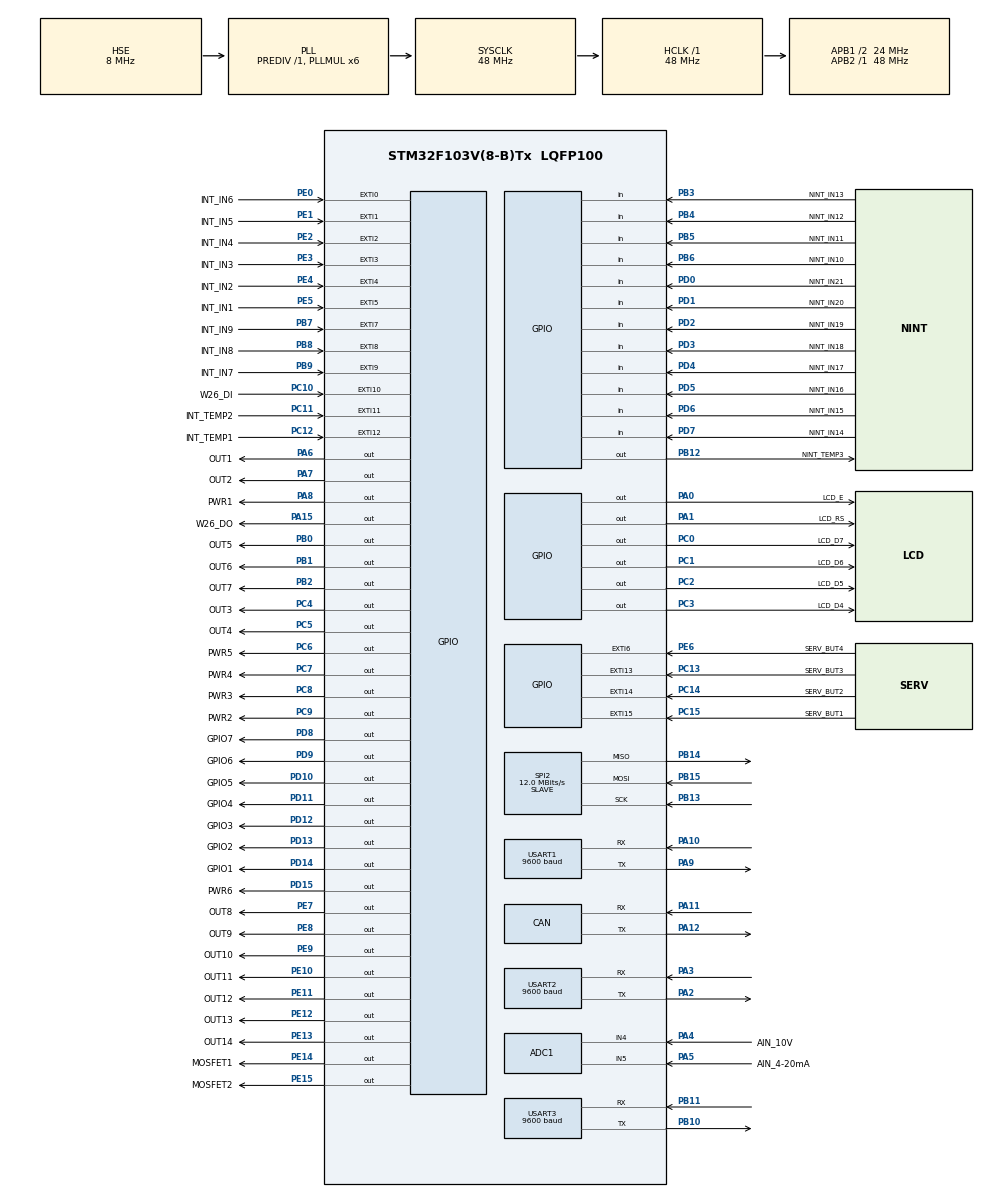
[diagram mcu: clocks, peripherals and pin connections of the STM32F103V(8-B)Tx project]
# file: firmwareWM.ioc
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ADC1.Channel-0\#ChannelRegularConversion=ADC_CHANNEL_TEMPSENSOR
ADC1.Channel-1\#ChannelInjectedConversion=ADC_CHANNEL_4
ADC1.Channel-2\#ChannelInjectedConversion=ADC_CHANNEL_5
ADC1.Channel-3\#ChannelInjectedConversion=ADC_CHANNEL_TEMPSENSOR
ADC1.Channel-4\#ChannelInjectedConversion=ADC_CHANNEL_VREFINT
ADC1.ContinuousConvMode=DISABLE
ADC1.DataAlign=ADC_DATAALIGN_RIGHT
ADC1.DiscontinuousConvMode=DISABLE
ADC1.EnableAnalogWatchDog=false
ADC1.EnableRegularConversion=ENABLE
ADC1.ExternalTrigConv=ADC_SOFTWARE_START
ADC1.ExternalTrigInjecConv=ADC_INJECTED_SOFTWARE_START
ADC1.InjNumberOfConversion=4
ADC1.InjectedConvMode=None
ADC1.InjectedOffset-1\#ChannelInjectedConversion=0
ADC1.InjectedOffset-2\#ChannelInjectedConversion=0
ADC1.InjectedOffset-3\#ChannelInjectedConversion=0
ADC1.InjectedOffset-4\#ChannelInjectedConversion=0
ADC1.NbrOfConversion=1
ADC1.Rank-0\#ChannelRegularConversion=1
ADC1.Rank-1\#ChannelInjectedConversion=1
ADC1.Rank-2\#ChannelInjectedConversion=2
ADC1.Rank-3\#ChannelInjectedConversion=3
ADC1.Rank-4\#ChannelInjectedConversion=4
ADC1.SamplingTime-0\#ChannelRegularConversion=ADC_SAMPLETIME_1CYCLE_5
ADC1.SamplingTime-1\#ChannelInjectedConversion=ADC_SAMPLETIME_1CYCLE_5
ADC1.SamplingTime-2\#ChannelInjectedConversion=ADC_SAMPLETIME_1CYCLE_5
ADC1.SamplingTime-3\#ChannelInjectedConversion=ADC_SAMPLETIME_7CYCLES_5
ADC1.SamplingTime-4\#ChannelInjectedConversion=ADC_SAMPLETIME_1CYCLE_5
ADC1.ScanConvMode=ADC_SCAN_ENABLE
ADC1.master=1
CAN.CalculateTimeBit=2000
CAN.CalculateTimeQuantum=666.6666666666666
IWDG.Prescaler=IWDG_PRESCALER_128
IWDG.Reload=1500
Mcu.Family=STM32F1
Mcu.Name=STM32F103V(8-B)Tx
Mcu.Package=LQFP100
NVIC.EXTI0_IRQn=true\:2\:0\:true\:false\:true\:true
NVIC.EXTI15_10_IRQn=true\:2\:0\:true\:false\:true\:true
NVIC.EXTI1_IRQn=true\:2\:0\:true\:false\:true\:true
NVIC.EXTI2_IRQn=true\:2\:0\:true\:false\:true\:true
NVIC.EXTI3_IRQn=true\:2\:0\:true\:false\:true\:true
NVIC.EXTI4_IRQn=true\:2\:0\:true\:false\:true\:true
NVIC.EXTI9_5_IRQn=true\:2\:0\:true\:false\:true\:true
NVIC.PriorityGroup=NVIC_PRIORITYGROUP_4
NVIC.TIM3_IRQn=true\:1\:0\:true\:false\:true\:true
NVIC.USART1_IRQn=true\:0\:0\:false\:false\:true\:true
NVIC.WWDG_IRQn=true\:0\:0\:false\:false\:true\:true
OSC_IN.Mode=HSE-External-Oscillator
OSC_IN.Signal=RCC_OSC_IN
OSC_OUT.Mode=HSE-External-Oscillator
OSC_OUT.Signal=RCC_OSC_OUT
PA0-WKUP.GPIO_Label=LCD_E
PA0-WKUP.Signal=GPIO_Output
PA1.GPIO_Label=LCD_RS
PA1.Signal=GPIO_Output
PA10.Mode=Asynchronous
PA10.Signal=USART1_RX
PA11.Mode=Master
PA11.Signal=CAN_RX
PA12.Mode=Master
PA12.Signal=CAN_TX
PA13.GPIO_Label=SWDIO
PA13.Mode=Serial_Wire
PA13.Signal=SYS_JTMS-SWDIO
PA14.GPIO_Label=SWCLK
PA14.Mode=Serial_Wire
PA14.Signal=SYS_JTCK-SWCLK
PA15.GPIO_Label=W26_DO
PA15.Signal=GPIO_Output
PA2.Mode=Asynchronous
PA2.Signal=USART2_TX
PA3.Mode=Asynchronous
PA3.Signal=USART2_RX
PA4.GPIO_Label=AIN_10V
PA4.Signal=ADCx_IN4
PA5.GPIO_Label=AIN_4-20mA
PA5.Signal=ADCx_IN5
PA6.GPIO_Label=OUT1
PA6.Signal=GPIO_Output
PA7.GPIO_Label=OUT2
PA7.Signal=GPIO_Output
PA8.GPIO_Label=PWR1
PA8.Signal=GPIO_Output
PA9.Mode=Asynchronous
PA9.Signal=USART1_TX
PB0.GPIO_Label=OUT5
PB0.Signal=GPIO_Output
PB1.GPIO_Label=OUT6
PB1.Signal=GPIO_Output
PB10.Mode=Asynchronous
PB10.Signal=USART3_TX
PB11.Mode=Asynchronous
PB11.Signal=USART3_RX
PB12.GPIO_Label=NINT_TEMP3
PB12.Signal=GPIO_Output
PB13.Mode=Full_Duplex_Slave
PB13.Signal=SPI2_SCK
PB14.Mode=Full_Duplex_Slave
PB14.Signal=SPI2_MISO
PB15.Mode=Full_Duplex_Slave
PB15.Signal=SPI2_MOSI
PB2.GPIO_Label=OUT7
PB2.Signal=GPIO_Output
PB3.GPIO_Label=NINT_IN13
PB3.GPIO_PuPd=GPIO_PULLUP
PB3.Signal=GPIO_Input
PB4.GPIO_Label=NINT_IN12
PB4.GPIO_PuPd=GPIO_PULLUP
PB4.Signal=GPIO_Input
PB5.GPIO_Label=NINT_IN11
PB5.GPIO_PuPd=GPIO_PULLUP
PB5.Signal=GPIO_Input
PB6.GPIO_Label=NINT_IN10
PB6.GPIO_PuPd=GPIO_PULLUP
PB6.Signal=GPIO_Input
PB7.GPIO_Label=INT_IN9
PB7.GPIO_PuPd=GPIO_PULLUP
PB7.Signal=GPXTI7
PB8.GPIO_Label=INT_IN8
PB8.GPIO_PuPd=GPIO_PULLUP
PB8.Signal=GPXTI8
PB9.GPIO_Label=INT_IN7
PB9.GPIO_PuPd=GPIO_PULLUP
PB9.Signal=GPXTI9
PC0.GPIO_Label=LCD_D7
PC0.Signal=GPIO_Output
PC1.GPIO_Label=LCD_D6
PC1.Signal=GPIO_Output
PC10.GPIO_Label=W26_DI
PC10.GPIO_PuPd=GPIO_PULLUP
PC10.Signal=GPXTI10
PC11.GPIO_Label=INT_TEMP2
PC11.GPIO_PuPd=GPIO_PULLUP
PC11.Signal=GPXTI11
PC12.GPIO_Label=INT_TEMP1
PC12.GPIO_PuPd=GPIO_PULLUP
PC12.Signal=GPXTI12
PC13-TAMPER-RTC.GPIO_Label=SERV_BUT3
PC13-TAMPER-RTC.GPIO_PuPd=GPIO_PULLUP
PC13-TAMPER-RTC.Signal=GPXTI13
PC14-OSC32_IN.GPIO_Label=SERV_BUT2
PC14-OSC32_IN.GPIO_PuPd=GPIO_PULLUP
PC14-OSC32_IN.Signal=GPXTI14
PC15-OSC32_OUT.GPIO_Label=SERV_BUT1
PC15-OSC32_OUT.GPIO_PuPd=GPIO_PULLUP
PC15-OSC32_OUT.Signal=GPXTI15
PC2.GPIO_Label=LCD_D5
PC2.Signal=GPIO_Output
PC3.GPIO_Label=LCD_D4
PC3.Signal=GPIO_Output
PC4.GPIO_Label=OUT3
PC4.Signal=GPIO_Output
PC5.GPIO_Label=OUT4
PC5.Signal=GPIO_Output
PC6.GPIO_Label=PWR5
PC6.Signal=GPIO_Output
PC7.GPIO_Label=PWR4
PC7.Signal=GPIO_Output
PC8.GPIO_Label=PWR3
PC8.Signal=GPIO_Output
PC9.GPIO_Label=PWR2
PC9.Signal=GPIO_Output
PD0.GPIO_Label=NINT_IN21
PD0.GPIO_PuPd=GPIO_PULLUP
PD0.Signal=GPIO_Input
PD1.GPIO_Label=NINT_IN20
PD1.GPIO_PuPd=GPIO_PULLUP
PD1.Signal=GPIO_Input
PD10.GPIO_Label=GPIO5
PD10.Signal=GPIO_Output
PD11.GPIO_Label=GPIO4
PD11.Signal=GPIO_Output
PD12.GPIO_Label=GPIO3
PD12.Signal=GPIO_Output
PD13.GPIO_Label=GPIO2
PD13.Signal=GPIO_Output
PD14.GPIO_Label=GPIO1
PD14.Signal=GPIO_Output
PD15.GPIO_Label=PWR6
PD15.Signal=GPIO_Output
PD2.GPIO_Label=NINT_IN19
PD2.GPIO_PuPd=GPIO_PULLUP
PD2.Signal=GPIO_Input
PD3.GPIO_Label=NINT_IN18
PD3.GPIO_PuPd=GPIO_PULLUP
PD3.Signal=GPIO_Input
PD4.GPIO_Label=NINT_IN17
PD4.GPIO_PuPd=GPIO_PULLUP
PD4.Signal=GPIO_Input
PD5.GPIO_Label=NINT_IN16
PD5.GPIO_PuPd=GPIO_PULLUP
PD5.Signal=GPIO_Input
PD6.GPIO_Label=NINT_IN15
PD6.GPIO_PuPd=GPIO_PULLUP
PD6.Signal=GPIO_Input
PD7.GPIO_Label=NINT_IN14
PD7.GPIO_PuPd=GPIO_PULLUP
PD7.Signal=GPIO_Input
PD8.GPIO_Label=GPIO7
PD8.Signal=GPIO_Output
PD9.GPIO_Label=GPIO6
PD9.Signal=GPIO_Output
PE0.GPIO_Label=INT_IN6
PE0.GPIO_PuPd=GPIO_PULLUP
PE0.Signal=GPXTI0
PE1.GPIO_Label=INT_IN5
PE1.GPIO_PuPd=GPIO_PULLUP
PE1.Signal=GPXTI1
PE10.GPIO_Label=OUT11
PE10.Signal=GPIO_Output
PE11.GPIO_Label=OUT12
PE11.Signal=GPIO_Output
PE12.GPIO_Label=OUT13
PE12.Signal=GPIO_Output
PE13.GPIO_Label=OUT14
PE13.Signal=GPIO_Output
PE14.GPIO_Label=MOSFET1
PE14.Signal=GPIO_Output
PE15.GPIO_Label=MOSFET2
PE15.Signal=GPIO_Output
PE2.GPIO_Label=INT_IN4
PE2.GPIO_PuPd=GPIO_NOPULL
PE2.Signal=GPXTI2
PE3.GPIO_Label=INT_IN3
PE3.GPIO_PuPd=GPIO_NOPULL
PE3.Signal=GPXTI3
PE4.GPIO_Label=INT_IN2
PE4.GPIO_PuPd=GPIO_NOPULL
PE4.Signal=GPXTI4
PE5.GPIO_Label=INT_IN1
PE5.Signal=GPXTI5
PE6.GPIO_Label=SERV_BUT4
PE6.GPIO_PuPd=GPIO_PULLUP
PE6.Signal=GPXTI6
PE7.GPIO_Label=OUT8
PE7.Signal=GPIO_Output
PE8.GPIO_Label=OUT9
PE8.Signal=GPIO_Output
PE9.GPIO_Label=OUT10
PE9.Signal=GPIO_Output
ProjectManager.HeapSize=0x200
ProjectManager.StackSize=0x400
ProjectManager.TargetToolchain=EWARM
RCC.ADCPresc=RCC_ADCPCLK2_DIV4
RCC.AHBFreq_Value=48000000
RCC.APB1CLKDivider=RCC_HCLK_DIV2
RCC.APB1Freq_Value=24000000
RCC.APB1TimFreq_Value=48000000
RCC.APB2Freq_Value=48000000
RCC.APB2TimFreq_Value=48000000
RCC.HCLKFreq_Value=48000000
RCC.PLLMUL=RCC_PLL_MUL6
RCC.PLLSourceVirtual=RCC_PLLSOURCE_HSE
RCC.SYSCLKFreq_VALUE=48000000
RCC.SYSCLKSource=RCC_SYSCLKSOURCE_PLLCLK
RCC.USBFreq_Value=48000000
SH.ADCx_IN4.0=ADC1_IN4,IN4
SH.ADCx_IN5.0=ADC1_IN5,IN5
SPI2.BaudRatePrescaler=SPI_BAUDRATEPRESCALER_2
SPI2.CalculateBaudRate=12.0 MBits/s
SPI2.Direction=SPI_DIRECTION_2LINES
SPI2.Mode=SPI_MODE_SLAVE
SPI2.VirtualType=VM_SLAVE
TIM3.ClockDivision=TIM_CLOCKDIVISION_DIV4
TIM3.Period=999
TIM3.Prescaler=47
USART1.BaudRate=9600
USART1.VirtualMode=VM_ASYNC
USART2.BaudRate=9600
USART2.VirtualMode=VM_ASYNC
USART3.BaudRate=9600
USART3.VirtualMode=VM_ASYNC
VP_ADC1_TempSens_Input.Mode=IN-TempSens
VP_ADC1_Vref_Input.Mode=IN-Vrefint
VP_CRC_VS_CRC.Mode=CRC_Activate
VP_IWDG_VS_IWDG.Mode=IWDG_Activate
VP_TIM3_VS_ClockSourceINT.Mode=Internal
VP_WWDG_VS_WWDG.Mode=WWDG_Activate
WWDG.Counter=127
WWDG.EWIMode=WWDG_EWI_ENABLE
WWDG.Prescaler=WWDG_PRESCALER_8
WWDG.Window=127
board=firmwareWM

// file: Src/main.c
/**
  ******************************************************************************
  * File Name          : main.c
  * Description        : Main program body
  ******************************************************************************
  ** This notice applies to any and all portions of this file
  * that are not between comment pairs USER CODE BEGIN and
  * USER CODE END. Other portions of this file, whether
  * inserted by the user or by software development tools
  * are owned by their respective copyright owners.
  *
  * COPYRIGHT(c) 2017 STMicroelectronics
  *
  * Redistribution and use in source and binary forms, with or without modification,
  * are permitted provided that the following conditions are met:
  *   1. Redistributions of source code must retain the above copyright notice,
  *      this list of conditions and the following disclaimer.
  *   2. Redistributions in binary form must reproduce the above copyright notice,
  *      this list of conditions and the following disclaimer in the documentation
  *      and/or other materials provided with the distribution.
  *   3. Neither the name of STMicroelectronics nor the names of its contributors
  *      may be used to endorse or promote products derived from this software
  *      without specific prior written permission.
  *
  * THIS SOFTWARE IS PROVIDED BY THE COPYRIGHT HOLDERS AND CONTRIBUTORS "AS IS"
  * AND ANY EXPRESS OR IMPLIED WARRANTIES, INCLUDING, BUT NOT LIMITED TO, THE
  * IMPLIED WARRANTIES OF MERCHANTABILITY AND FITNESS FOR A PARTICULAR PURPOSE ARE
  * DISCLAIMED. IN NO EVENT SHALL THE COPYRIGHT HOLDER OR CONTRIBUTORS BE LIABLE
  * FOR ANY DIRECT, INDIRECT, INCIDENTAL, SPECIAL, EXEMPLARY, OR CONSEQUENTIAL
  * DAMAGES (INCLUDING, BUT NOT LIMITED TO, PROCUREMENT OF SUBSTITUTE GOODS OR
  * SERVICES; LOSS OF USE, DATA, OR PROFITS; OR BUSINESS INTERRUPTION) HOWEVER
  * CAUSED AND ON ANY THEORY OF LIABILITY, WHETHER IN CONTRACT, STRICT LIABILITY,
  * OR TORT (INCLUDING NEGLIGENCE OR OTHERWISE) ARISING IN ANY WAY OUT OF THE USE
  * OF THIS SOFTWARE, EVEN IF ADVISED OF THE POSSIBILITY OF SUCH DAMAGE.
  *
  ******************************************************************************
  */

#include "main.h"
#include "stm32f1xx_hal.h"

/* USER CODE BEGIN Includes */
#include "mainLogic.h"
#include "tm_stm32_hd44780.h"

/* USER CODE END Includes */

ADC_HandleTypeDef hadc1;

CAN_HandleTypeDef hcan;

CRC_HandleTypeDef hcrc;

IWDG_HandleTypeDef hiwdg;

SPI_HandleTypeDef hspi2;

TIM_HandleTypeDef htim3;

UART_HandleTypeDef huart1;
UART_HandleTypeDef huart2;
UART_HandleTypeDef huart3;

WWDG_HandleTypeDef hwwdg;

/* USER CODE BEGIN PV */
/* Private variables ---------------------------------------------------------*/

/* USER CODE END PV */

void SystemClock_Config(void);
static void MX_GPIO_Init(void);
static void MX_ADC1_Init(void);
static void MX_CAN_Init(void);
static void MX_CRC_Init(void);
static void MX_SPI2_Init(void);
static void MX_TIM3_Init(void);
static void MX_USART1_UART_Init(void);
static void MX_USART2_UART_Init(void);
static void MX_USART3_UART_Init(void);
static void MX_IWDG_Init(void);
static void MX_WWDG_Init(void);

/* USER CODE BEGIN PFP */
/* Private function prototypes -----------------------------------------------*/

/* USER CODE END PFP */

/* USER CODE BEGIN 0 */

void readAdc(uint16_t * suppVolCH4, uint16_t * adcCH5, uint16_t * adcTempMCU, uint16_t * intRef) {
  HAL_ADCEx_InjectedPollForConversion(&hadc1, 100);
  *suppVolCH4 = HAL_ADCEx_InjectedGetValue(&hadc1, ADC_INJECTED_RANK_1);
  *adcCH5 = HAL_ADCEx_InjectedGetValue(&hadc1, ADC_INJECTED_RANK_2);
  *adcTempMCU = HAL_ADCEx_InjectedGetValue(&hadc1, ADC_INJECTED_RANK_3);
  *intRef = HAL_ADCEx_InjectedGetValue(&hadc1, ADC_INJECTED_RANK_4);
  HAL_ADCEx_InjectedStop(&hadc1);
  HAL_ADCEx_InjectedStart(&hadc1);
}

void refreshWatchDogs (void) {
  HAL_WWDG_Refresh(&hwwdg);           // 43.9 ms to reset (IRQ handler used to inform)
  HAL_IWDG_Refresh(&hiwdg);           // 3000 ms to reset (no handler)
}

/* USER CODE END 0 */

int main(void)
{

  /* MCU Configuration----------------------------------------------------------*/

  /* Reset of all peripherals, Initializes the Flash interface and the Systick. */
  HAL_Init();

  /* USER CODE BEGIN Init */
  MX_GPIO_Init();
  TM_HD44780_Init(16, 2, 1);
  /* USER CODE END Init */

  /* Configure the system clock */
  SystemClock_Config();

  /* Initialize all configured peripherals */
  MX_GPIO_Init();
  MX_ADC1_Init();
  MX_CAN_Init();
  MX_CRC_Init();
  MX_SPI2_Init();
  MX_TIM3_Init();
  MX_USART1_UART_Init();
  MX_USART2_UART_Init();
  MX_USART3_UART_Init();
  MX_IWDG_Init();
  MX_WWDG_Init();

  /* Infinite loop */
  /* USER CODE BEGIN WHILE */
  refreshWatchDogs();
  mainSetup();
  HAL_TIM_Base_Start_IT(&htim3);
  HAL_ADCEx_InjectedStart(&hadc1);
  while (1)
  {
    mainLoop();

  /* USER CODE END WHILE */

  }

}

/** System Clock Configuration
*/
void SystemClock_Config(void)
{

  RCC_OscInitTypeDef RCC_OscInitStruct;
  RCC_ClkInitTypeDef RCC_ClkInitStruct;
  RCC_PeriphCLKInitTypeDef PeriphClkInit;

    /**Initializes the CPU, AHB and APB busses clocks
    */
  RCC_OscInitStruct.OscillatorType = RCC_OSCILLATORTYPE_LSI|RCC_OSCILLATORTYPE_HSE;
  RCC_OscInitStruct.HSEState = RCC_HSE_ON;
  RCC_OscInitStruct.HSEPredivValue = RCC_HSE_PREDIV_DIV1;
  RCC_OscInitStruct.HSIState = RCC_HSI_ON;
  RCC_OscInitStruct.LSIState = RCC_LSI_ON;
  RCC_OscInitStruct.PLL.PLLState = RCC_PLL_ON;
  RCC_OscInitStruct.PLL.PLLSource = RCC_PLLSOURCE_HSE;
  RCC_OscInitStruct.PLL.PLLMUL = RCC_PLL_MUL6;
  if (HAL_RCC_OscConfig(&RCC_OscInitStruct) != HAL_OK)
  {
    _Error_Handler(__FILE__, __LINE__);
  }

    /**Initializes the CPU, AHB and APB busses clocks
    */
  RCC_ClkInitStruct.ClockType = RCC_CLOCKTYPE_HCLK|RCC_CLOCKTYPE_SYSCLK
                              |RCC_CLOCKTYPE_PCLK1|RCC_CLOCKTYPE_PCLK2;
  RCC_ClkInitStruct.SYSCLKSource = RCC_SYSCLKSOURCE_PLLCLK;
  RCC_ClkInitStruct.AHBCLKDivider = RCC_SYSCLK_DIV1;
  RCC_ClkInitStruct.APB1CLKDivider = RCC_HCLK_DIV2;
  RCC_ClkInitStruct.APB2CLKDivider = RCC_HCLK_DIV1;

  if (HAL_RCC_ClockConfig(&RCC_ClkInitStruct, FLASH_LATENCY_1) != HAL_OK)
  {
    _Error_Handler(__FILE__, __LINE__);
  }

  PeriphClkInit.PeriphClockSelection = RCC_PERIPHCLK_ADC;
  PeriphClkInit.AdcClockSelection = RCC_ADCPCLK2_DIV4;
  if (HAL_RCCEx_PeriphCLKConfig(&PeriphClkInit) != HAL_OK)
  {
    _Error_Handler(__FILE__, __LINE__);
  }

    /**Configure the Systick interrupt time
    */
  HAL_SYSTICK_Config(HAL_RCC_GetHCLKFreq()/1000);

    /**Configure the Systick
    */
  HAL_SYSTICK_CLKSourceConfig(SYSTICK_CLKSOURCE_HCLK);

  /* SysTick_IRQn interrupt configuration */
  HAL_NVIC_SetPriority(SysTick_IRQn, 0, 0);
}

/* ADC1 init function */
static void MX_ADC1_Init(void)
{

  ADC_ChannelConfTypeDef sConfig;
  ADC_InjectionConfTypeDef sConfigInjected;

    /**Common config
    */
  hadc1.Instance = ADC1;
  hadc1.Init.ScanConvMode = ADC_SCAN_ENABLE;
  hadc1.Init.ContinuousConvMode = DISABLE;
  hadc1.Init.DiscontinuousConvMode = DISABLE;
  hadc1.Init.ExternalTrigConv = ADC_SOFTWARE_START;
  hadc1.Init.DataAlign = ADC_DATAALIGN_RIGHT;
  hadc1.Init.NbrOfConversion = 1;
  if (HAL_ADC_Init(&hadc1) != HAL_OK)
  {
    _Error_Handler(__FILE__, __LINE__);
  }

    /**Configure Regular Channel
    */
  sConfig.Channel = ADC_CHANNEL_TEMPSENSOR;
  sConfig.Rank = 1;
  sConfig.SamplingTime = ADC_SAMPLETIME_1CYCLE_5;
  if (HAL_ADC_ConfigChannel(&hadc1, &sConfig) != HAL_OK)
  {
    _Error_Handler(__FILE__, __LINE__);
  }

    /**Configure Injected Channel
    */
  sConfigInjected.InjectedChannel = ADC_CHANNEL_4;
  sConfigInjected.InjectedRank = 1;
  sConfigInjected.InjectedNbrOfConversion = 4;
  sConfigInjected.InjectedSamplingTime = ADC_SAMPLETIME_1CYCLE_5;
  sConfigInjected.ExternalTrigInjecConv = ADC_INJECTED_SOFTWARE_START;
  sConfigInjected.AutoInjectedConv = DISABLE;
  sConfigInjected.InjectedDiscontinuousConvMode = DISABLE;
  sConfigInjected.InjectedOffset = 0;
  if (HAL_ADCEx_InjectedConfigChannel(&hadc1, &sConfigInjected) != HAL_OK)
  {
    _Error_Handler(__FILE__, __LINE__);
  }

    /**Configure Injected Channel
    */
  sConfigInjected.InjectedChannel = ADC_CHANNEL_5;
  sConfigInjected.InjectedRank = 2;
  if (HAL_ADCEx_InjectedConfigChannel(&hadc1, &sConfigInjected) != HAL_OK)
  {
    _Error_Handler(__FILE__, __LINE__);
  }

    /**Configure Injected Channel
    */
  sConfigInjected.InjectedChannel = ADC_CHANNEL_TEMPSENSOR;
  sConfigInjected.InjectedRank = 3;
  sConfigInjected.InjectedSamplingTime = ADC_SAMPLETIME_7CYCLES_5;
  if (HAL_ADCEx_InjectedConfigChannel(&hadc1, &sConfigInjected) != HAL_OK)
  {
    _Error_Handler(__FILE__, __LINE__);
  }

    /**Configure Injected Channel
    */
  sConfigInjected.InjectedChannel = ADC_CHANNEL_VREFINT;
  sConfigInjected.InjectedRank = 4;
  sConfigInjected.InjectedSamplingTime = ADC_SAMPLETIME_1CYCLE_5;
  if (HAL_ADCEx_InjectedConfigChannel(&hadc1, &sConfigInjected) != HAL_OK)
  {
    _Error_Handler(__FILE__, __LINE__);
  }

}

/* CAN init function */
static void MX_CAN_Init(void)
{

  hcan.Instance = CAN1;
  hcan.Init.Prescaler = 16;
  hcan.Init.Mode = CAN_MODE_NORMAL;
  hcan.Init.SJW = CAN_SJW_1TQ;
  hcan.Init.BS1 = CAN_BS1_1TQ;
  hcan.Init.BS2 = CAN_BS2_1TQ;
  hcan.Init.TTCM = DISABLE;
  hcan.Init.ABOM = DISABLE;
  hcan.Init.AWUM = DISABLE;
  hcan.Init.NART = DISABLE;
  hcan.Init.RFLM = DISABLE;
  hcan.Init.TXFP = DISABLE;
  if (HAL_CAN_Init(&hcan) != HAL_OK)
  {
    _Error_Handler(__FILE__, __LINE__);
  }

}

/* CRC init function */
static void MX_CRC_Init(void)
{

  hcrc.Instance = CRC;
  if (HAL_CRC_Init(&hcrc) != HAL_OK)
  {
    _Error_Handler(__FILE__, __LINE__);
  }

}

/* IWDG init function */
static void MX_IWDG_Init(void)
{

  hiwdg.Instance = IWDG;
  hiwdg.Init.Prescaler = IWDG_PRESCALER_32;
  hiwdg.Init.Reload = 4000;
  if (HAL_IWDG_Init(&hiwdg) != HAL_OK)
  {
    _Error_Handler(__FILE__, __LINE__);
  }

}

/* SPI2 init function */
static void MX_SPI2_Init(void)
{

  /* SPI2 parameter configuration*/
  hspi2.Instance = SPI2;
  hspi2.Init.Mode = SPI_MODE_SLAVE;
  hspi2.Init.Direction = SPI_DIRECTION_2LINES;
  hspi2.Init.DataSize = SPI_DATASIZE_8BIT;
  hspi2.Init.CLKPolarity = SPI_POLARITY_LOW;
  hspi2.Init.CLKPhase = SPI_PHASE_1EDGE;
  hspi2.Init.NSS = SPI_NSS_SOFT;
  hspi2.Init.BaudRatePrescaler = SPI_BAUDRATEPRESCALER_2;
  hspi2.Init.FirstBit = SPI_FIRSTBIT_MSB;
  hspi2.Init.TIMode = SPI_TIMODE_DISABLE;
  hspi2.Init.CRCCalculation = SPI_CRCCALCULATION_DISABLE;
  hspi2.Init.CRCPolynomial = 10;
  if (HAL_SPI_Init(&hspi2) != HAL_OK)
  {
    _Error_Handler(__FILE__, __LINE__);
  }

}

/* TIM3 init function */
static void MX_TIM3_Init(void)
{

  TIM_ClockConfigTypeDef sClockSourceConfig;
  TIM_MasterConfigTypeDef sMasterConfig;

  htim3.Instance = TIM3;
  htim3.Init.Prescaler = 47;
  htim3.Init.CounterMode = TIM_COUNTERMODE_UP;
  htim3.Init.Period = 999;
  htim3.Init.ClockDivision = TIM_CLOCKDIVISION_DIV4;
  htim3.Init.AutoReloadPreload = TIM_AUTORELOAD_PRELOAD_DISABLE;
  if (HAL_TIM_Base_Init(&htim3) != HAL_OK)
  {
    _Error_Handler(__FILE__, __LINE__);
  }

  sClockSourceConfig.ClockSource = TIM_CLOCKSOURCE_INTERNAL;
  if (HAL_TIM_ConfigClockSource(&htim3, &sClockSourceConfig) != HAL_OK)
  {
    _Error_Handler(__FILE__, __LINE__);
  }

  sMasterConfig.MasterOutputTrigger = TIM_TRGO_RESET;
  sMasterConfig.MasterSlaveMode = TIM_MASTERSLAVEMODE_DISABLE;
  if (HAL_TIMEx_MasterConfigSynchronization(&htim3, &sMasterConfig) != HAL_OK)
  {
    _Error_Handler(__FILE__, __LINE__);
  }

}

/* USART1 init function */
static void MX_USART1_UART_Init(void)
{

  huart1.Instance = USART1;
  huart1.Init.BaudRate = 9600;
  huart1.Init.WordLength = UART_WORDLENGTH_8B;
  huart1.Init.StopBits = UART_STOPBITS_1;
  huart1.Init.Parity = UART_PARITY_NONE;
  huart1.Init.Mode = UART_MODE_TX_RX;
  huart1.Init.HwFlowCtl = UART_HWCONTROL_NONE;
  huart1.Init.OverSampling = UART_OVERSAMPLING_16;
  if (HAL_UART_Init(&huart1) != HAL_OK)
  {
    _Error_Handler(__FILE__, __LINE__);
  }

}

/* USART2 init function */
static void MX_USART2_UART_Init(void)
{

  huart2.Instance = USART2;
  huart2.Init.BaudRate = 9600;
  huart2.Init.WordLength = UART_WORDLENGTH_8B;
  huart2.Init.StopBits = UART_STOPBITS_1;
  huart2.Init.Parity = UART_PARITY_NONE;
  huart2.Init.Mode = UART_MODE_TX_RX;
  huart2.Init.HwFlowCtl = UART_HWCONTROL_NONE;
  huart2.Init.OverSampling = UART_OVERSAMPLING_16;
  if (HAL_UART_Init(&huart2) != HAL_OK)
  {
    _Error_Handler(__FILE__, __LINE__);
  }

}

/* USART3 init function */
static void MX_USART3_UART_Init(void)
{

  huart3.Instance = USART3;
  huart3.Init.BaudRate = 9600;
  huart3.Init.WordLength = UART_WORDLENGTH_8B;
  huart3.Init.StopBits = UART_STOPBITS_1;
  huart3.Init.Parity = UART_PARITY_NONE;
  huart3.Init.Mode = UART_MODE_TX_RX;
  huart3.Init.HwFlowCtl = UART_HWCONTROL_NONE;
  huart3.Init.OverSampling = UART_OVERSAMPLING_16;
  if (HAL_UART_Init(&huart3) != HAL_OK)
  {
    _Error_Handler(__FILE__, __LINE__);
  }

}

/* WWDG init function */
static void MX_WWDG_Init(void)
{

  hwwdg.Instance = WWDG;
  hwwdg.Init.Prescaler = WWDG_PRESCALER_8;
  hwwdg.Init.Window = 127;
  hwwdg.Init.Counter = 127;
  hwwdg.Init.EWIMode = WWDG_EWI_ENABLE;
  if (HAL_WWDG_Init(&hwwdg) != HAL_OK)
  {
    _Error_Handler(__FILE__, __LINE__);
  }

}

/** Configure pins as
        * Analog
        * Input
        * Output
        * EVENT_OUT
        * EXTI
*/
static void MX_GPIO_Init(void)
{

  GPIO_InitTypeDef GPIO_InitStruct;

  /* GPIO Ports Clock Enable */
  __HAL_RCC_GPIOE_CLK_ENABLE();
  __HAL_RCC_GPIOC_CLK_ENABLE();
  __HAL_RCC_GPIOA_CLK_ENABLE();
  __HAL_RCC_GPIOB_CLK_ENABLE();
  __HAL_RCC_GPIOD_CLK_ENABLE();

  /*Configure GPIO pin Output Level */
  HAL_GPIO_WritePin(GPIOC, LCD_D7_Pin|LCD_D6_Pin|LCD_D5_Pin|LCD_D4_Pin
                          |OUT3_Pin|OUT4_Pin|PWR5_Pin|PWR4_Pin
                          |PWR3_Pin|PWR2_Pin, GPIO_PIN_RESET);

  /*Configure GPIO pin Output Level */
  HAL_GPIO_WritePin(GPIOA, LCD_E_Pin|LCD_RS_Pin|OUT1_Pin|OUT2_Pin
                          |PWR1_Pin|W26_DO_Pin, GPIO_PIN_RESET);

  /*Configure GPIO pin Output Level */
  HAL_GPIO_WritePin(GPIOB, OUT5_Pin|OUT6_Pin|OUT7_Pin, GPIO_PIN_RESET);

  /*Configure GPIO pin Output Level */
  HAL_GPIO_WritePin(GPIOE, OUT8_Pin|OUT9_Pin|OUT10_Pin|OUT11_Pin
                          |OUT12_Pin|OUT13_Pin|OUT14_Pin|MOSFET1_Pin
                          |MOSFET2_Pin, GPIO_PIN_RESET);

  /*Configure GPIO pin Output Level */
  HAL_GPIO_WritePin(GPIOD, GPIO7_Pin|GPIO6_Pin|GPIO5_Pin|GPIO4_Pin
                          |GPIO3_Pin|GPIO2_Pin|GPIO1_Pin|PWR6_Pin, GPIO_PIN_RESET);

  /*Configure GPIO pins : INT_IN4_Pin INT_IN3_Pin INT_IN2_Pin INT_IN1_Pin */
  GPIO_InitStruct.Pin = INT_IN4_Pin|INT_IN3_Pin|INT_IN2_Pin|INT_IN1_Pin;
  GPIO_InitStruct.Mode = GPIO_MODE_IT_RISING;
  GPIO_InitStruct.Pull = GPIO_NOPULL;
  HAL_GPIO_Init(GPIOE, &GPIO_InitStruct);

  /*Configure GPIO pin : SERV_BUT4_Pin */
  GPIO_InitStruct.Pin = SERV_BUT4_Pin;
  GPIO_InitStruct.Mode = GPIO_MODE_IT_RISING;
  GPIO_InitStruct.Pull = GPIO_PULLUP;
  HAL_GPIO_Init(SERV_BUT4_GPIO_Port, &GPIO_InitStruct);

  /*Configure GPIO pins : SERV_BUT3_Pin SERV_BUT2_Pin SERV_BUT1_Pin W26_DI_Pin */
  GPIO_InitStruct.Pin = SERV_BUT3_Pin|SERV_BUT2_Pin|SERV_BUT1_Pin|W26_DI_Pin;
  GPIO_InitStruct.Mode = GPIO_MODE_IT_RISING;
  GPIO_InitStruct.Pull = GPIO_PULLUP;
  HAL_GPIO_Init(GPIOC, &GPIO_InitStruct);

  /*Configure GPIO pins : LCD_D7_Pin LCD_D6_Pin LCD_D5_Pin LCD_D4_Pin
                           OUT3_Pin OUT4_Pin PWR5_Pin PWR4_Pin
                           PWR3_Pin PWR2_Pin */
  GPIO_InitStruct.Pin = LCD_D7_Pin|LCD_D6_Pin|LCD_D5_Pin|LCD_D4_Pin
                          |OUT3_Pin|OUT4_Pin|PWR5_Pin|PWR4_Pin
                          |PWR3_Pin|PWR2_Pin;
  GPIO_InitStruct.Mode = GPIO_MODE_OUTPUT_PP;
  GPIO_InitStruct.Speed = GPIO_SPEED_FREQ_LOW;
  HAL_GPIO_Init(GPIOC, &GPIO_InitStruct);

  /*Configure GPIO pins : LCD_E_Pin LCD_RS_Pin OUT1_Pin OUT2_Pin
                           PWR1_Pin W26_DO_Pin */
  GPIO_InitStruct.Pin = LCD_E_Pin|LCD_RS_Pin|OUT1_Pin|OUT2_Pin
                          |PWR1_Pin|W26_DO_Pin;
  GPIO_InitStruct.Mode = GPIO_MODE_OUTPUT_PP;
  GPIO_InitStruct.Speed = GPIO_SPEED_FREQ_LOW;
  HAL_GPIO_Init(GPIOA, &GPIO_InitStruct);

  /*Configure GPIO pins : OUT5_Pin OUT6_Pin OUT7_Pin */
  GPIO_InitStruct.Pin = OUT5_Pin|OUT6_Pin|OUT7_Pin;
  GPIO_InitStruct.Mode = GPIO_MODE_OUTPUT_PP;
  GPIO_InitStruct.Speed = GPIO_SPEED_FREQ_LOW;
  HAL_GPIO_Init(GPIOB, &GPIO_InitStruct);

  /*Configure GPIO pins : OUT8_Pin OUT9_Pin OUT10_Pin OUT11_Pin
                           OUT12_Pin OUT13_Pin OUT14_Pin MOSFET1_Pin
                           MOSFET2_Pin */
  GPIO_InitStruct.Pin = OUT8_Pin|OUT9_Pin|OUT10_Pin|OUT11_Pin
                          |OUT12_Pin|OUT13_Pin|OUT14_Pin|MOSFET1_Pin
                          |MOSFET2_Pin;
  GPIO_InitStruct.Mode = GPIO_MODE_OUTPUT_PP;
  GPIO_InitStruct.Speed = GPIO_SPEED_FREQ_LOW;
  HAL_GPIO_Init(GPIOE, &GPIO_InitStruct);

  /*Configure GPIO pins : NINT_TEMP3_Pin NINT_IN10_Pin NINT_IN9_Pin NINT_IN8_Pin */
  GPIO_InitStruct.Pin = NINT_TEMP3_Pin|NINT_IN10_Pin|NINT_IN9_Pin|NINT_IN8_Pin;
  GPIO_InitStruct.Mode = GPIO_MODE_INPUT;
  GPIO_InitStruct.Pull = GPIO_NOPULL;
  HAL_GPIO_Init(GPIOB, &GPIO_InitStruct);

  /*Configure GPIO pins : GPIO7_Pin GPIO6_Pin GPIO5_Pin GPIO4_Pin
                           GPIO3_Pin GPIO2_Pin GPIO1_Pin PWR6_Pin */
  GPIO_InitStruct.Pin = GPIO7_Pin|GPIO6_Pin|GPIO5_Pin|GPIO4_Pin
                          |GPIO3_Pin|GPIO2_Pin|GPIO1_Pin|PWR6_Pin;
  GPIO_InitStruct.Mode = GPIO_MODE_OUTPUT_PP;
  GPIO_InitStruct.Speed = GPIO_SPEED_FREQ_LOW;
  HAL_GPIO_Init(GPIOD, &GPIO_InitStruct);

  /*Configure GPIO pins : NINT_TEMP2_Pin NINT_TEMP1_Pin */
  GPIO_InitStruct.Pin = NINT_TEMP2_Pin|NINT_TEMP1_Pin;
  GPIO_InitStruct.Mode = GPIO_MODE_INPUT;
  GPIO_InitStruct.Pull = GPIO_NOPULL;
  HAL_GPIO_Init(GPIOC, &GPIO_InitStruct);

  /*Configure GPIO pins : NINT_IN21_Pin NINT_IN20_Pin NINT_IN19_Pin NINT_IN18_Pin
                           NINT_IN17_Pin NINT_IN16_Pin NINT_IN15_Pin NINT_IN14_Pin */
  GPIO_InitStruct.Pin = NINT_IN21_Pin|NINT_IN20_Pin|NINT_IN19_Pin|NINT_IN18_Pin
                          |NINT_IN17_Pin|NINT_IN16_Pin|NINT_IN15_Pin|NINT_IN14_Pin;
  GPIO_InitStruct.Mode = GPIO_MODE_INPUT;
  GPIO_InitStruct.Pull = GPIO_PULLUP;
  HAL_GPIO_Init(GPIOD, &GPIO_InitStruct);

  /*Configure GPIO pins : NINT_IN13_Pin NINT_IN12_Pin NINT_IN11_Pin */
  GPIO_InitStruct.Pin = NINT_IN13_Pin|NINT_IN12_Pin|NINT_IN11_Pin;
  GPIO_InitStruct.Mode = GPIO_MODE_INPUT;
  GPIO_InitStruct.Pull = GPIO_PULLUP;
  HAL_GPIO_Init(GPIOB, &GPIO_InitStruct);

  /*Configure GPIO pin : INT_IN7_Pin */
  GPIO_InitStruct.Pin = INT_IN7_Pin;
  GPIO_InitStruct.Mode = GPIO_MODE_IT_RISING;
  GPIO_InitStruct.Pull = GPIO_PULLUP;
  HAL_GPIO_Init(INT_IN7_GPIO_Port, &GPIO_InitStruct);

  /*Configure GPIO pins : NINT_IN6_Pin NINT_IN5_Pin */
  GPIO_InitStruct.Pin = NINT_IN6_Pin|NINT_IN5_Pin;
  GPIO_InitStruct.Mode = GPIO_MODE_INPUT;
  GPIO_InitStruct.Pull = GPIO_NOPULL;
  HAL_GPIO_Init(GPIOE, &GPIO_InitStruct);

  /* EXTI interrupt init*/
  HAL_NVIC_SetPriority(EXTI2_IRQn, 2, 0);
  HAL_NVIC_EnableIRQ(EXTI2_IRQn);

  HAL_NVIC_SetPriority(EXTI3_IRQn, 2, 0);
  HAL_NVIC_EnableIRQ(EXTI3_IRQn);

  HAL_NVIC_SetPriority(EXTI4_IRQn, 2, 0);
  HAL_NVIC_EnableIRQ(EXTI4_IRQn);

  HAL_NVIC_SetPriority(EXTI9_5_IRQn, 2, 0);
  HAL_NVIC_EnableIRQ(EXTI9_5_IRQn);

  HAL_NVIC_SetPriority(EXTI15_10_IRQn, 2, 0);
  HAL_NVIC_EnableIRQ(EXTI15_10_IRQn);

}

void _Error_Handler(char * file, int line)
{
  /* USER CODE BEGIN Error_Handler_Debug */
  NVIC_SystemReset();
  /* User can add his own implementation to report the HAL error return state */
  while(1)
  {
  }
  /* USER CODE END Error_Handler_Debug */
}

#ifdef USE_FULL_ASSERT

/**
   * @brief Reports the name of the source file and the source line number
   * where the assert_param error has occurred.
   * @param file: pointer to the source file name
   * @param line: assert_param error line source number
   * @retval None
   */
void assert_failed(uint8_t* file, uint32_t line)
{
  /* USER CODE BEGIN 6 */
  NVIC_SystemReset();
  /* User can add his own implementation to report the file name and line number,
    ex: printf("Wrong parameters value: file %s on line %d\r\n", file, line) */
  /* USER CODE END 6 */

}

#endif

/************************ (C) COPYRIGHT STMicroelectronics *****END OF FILE****/
